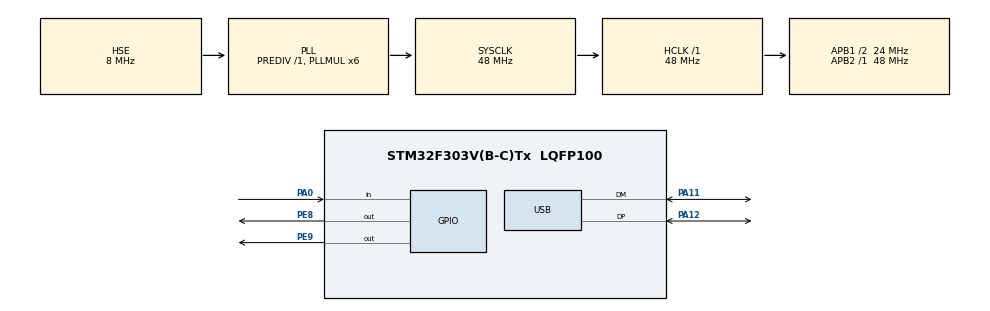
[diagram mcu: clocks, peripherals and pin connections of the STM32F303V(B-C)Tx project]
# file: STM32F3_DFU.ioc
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Mcu.Family=STM32F3
Mcu.Name=STM32F303V(B-C)Tx
Mcu.Package=LQFP100
NVIC.PriorityGroup=NVIC_PRIORITYGROUP_4
NVIC.USB_LP_CAN_RX0_IRQn=true\:0\:0\:false\:false\:true\:false\:true
PA0.GPIO_PuPd=GPIO_NOPULL
PA0.Signal=GPIO_Input
PA11.Mode=Device
PA11.Signal=USB_DM
PA12.Mode=Device
PA12.Signal=USB_DP
PE8.Signal=GPIO_Output
PE9.Signal=GPIO_Output
PF0-OSC_IN.Mode=HSE-External-Clock-Source
PF0-OSC_IN.Signal=RCC_OSC_IN
ProjectManager.HeapSize=0x200
ProjectManager.StackSize=0x400
ProjectManager.TargetToolchain=STM32CubeIDE
RCC.AHBFreq_Value=48000000
RCC.APB1CLKDivider=RCC_HCLK_DIV2
RCC.APB1Freq_Value=24000000
RCC.APB1TimFreq_Value=48000000
RCC.APB2Freq_Value=48000000
RCC.APB2TimFreq_Value=48000000
RCC.CortexFreq_Value=48000000
RCC.HCLKFreq_Value=48000000
RCC.HSE_VALUE=8000000
RCC.HSI_VALUE=8000000
RCC.LSE_VALUE=32768
RCC.PLLMUL=RCC_PLL_MUL6
RCC.SYSCLKFreq_VALUE=48000000
RCC.SYSCLKSourceVirtual=RCC_SYSCLKSOURCE_PLLCLK
RCC.USBFreq_Value=48000000
USB_DEVICE.CLASS_NAME_FS=DFU
USB_DEVICE.USBD_DFU_APP_DEFAULT_ADD=0x08006000
USB_DEVICE.USBD_DFU_MEDIA=@Internal Flash   /0x08000000/24*02Ka,232*02Kg
USB_DEVICE.VirtualMode=Dfu
USB_DEVICE.VirtualModeFS=Dfu_FS
VP_USB_DEVICE_VS_USB_DEVICE_DFU_FS.Mode=DFU_FS
board=custom

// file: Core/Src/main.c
/* USER CODE BEGIN Header */
/**
  ******************************************************************************
  * @file           : main.c
  * @brief          : Main program body
  ******************************************************************************
  * @attention
  *
  * <h2><center>&copy; Copyright (c) 2021 STMicroelectronics.
  * All rights reserved.</center></h2>
  *
  * This software component is licensed by ST under Ultimate Liberty license
  * SLA0044, the "License"; You may not use this file except in compliance with
  * the License. You may obtain a copy of the License at:
  *                             www.st.com/SLA0044
  *
  ******************************************************************************
  */
/* USER CODE END Header */
#include "main.h"
#include "usb_device.h"

/* USER CODE BEGIN PTD */
typedef  void (*pFunction)(void);
/* USER CODE END PTD */

void SystemClock_Config(void);
static void MX_GPIO_Init(void);

int main(void)
{
  /* USER CODE BEGIN 1 */
	  pFunction JumpToApplication;
	  uint32_t JumpAddress;
  /* USER CODE END 1 */

  /* MCU Configuration--------------------------------------------------------*/

  /* Reset of all peripherals, Initializes the Flash interface and the Systick. */
  HAL_Init();

  /* Configure the system clock */
  SystemClock_Config();

  /* Initialize all configured peripherals */
  MX_USB_DEVICE_Init();
  HAL_Delay(50);
  MX_GPIO_Init();
  /* USER CODE BEGIN 2 */
  if((GPIOA->IDR & GPIO_PIN_0) == 0)
  {
		JumpAddress = *(__IO uint32_t*) (USBD_DFU_APP_DEFAULT_ADD + 4);
		JumpToApplication = (pFunction) JumpAddress;

		/* Initialize user application's Stack Pointer */
		__set_MSP(*(__IO uint32_t*) USBD_DFU_APP_DEFAULT_ADD);
		JumpToApplication();
  }
  /* USER CODE END 2 */

  /* Infinite loop */
  while (1)
  {

    /* USER CODE BEGIN 3 */
	  GPIOE->ODR ^= (GPIO_PIN_9);
	  HAL_Delay(500);
  }
  /* USER CODE END 3 */
}

void SystemClock_Config(void)
{
  RCC_OscInitTypeDef RCC_OscInitStruct = {0};
  RCC_ClkInitTypeDef RCC_ClkInitStruct = {0};
  RCC_PeriphCLKInitTypeDef PeriphClkInit = {0};

  /** Initializes the RCC Oscillators according to the specified parameters
  * in the RCC_OscInitTypeDef structure.
  */
  RCC_OscInitStruct.OscillatorType = RCC_OSCILLATORTYPE_HSE;
  RCC_OscInitStruct.HSEState = RCC_HSE_BYPASS;
  RCC_OscInitStruct.HSEPredivValue = RCC_HSE_PREDIV_DIV1;
  RCC_OscInitStruct.HSIState = RCC_HSI_ON;
  RCC_OscInitStruct.PLL.PLLState = RCC_PLL_ON;
  RCC_OscInitStruct.PLL.PLLSource = RCC_PLLSOURCE_HSE;
  RCC_OscInitStruct.PLL.PLLMUL = RCC_PLL_MUL6;
  if (HAL_RCC_OscConfig(&RCC_OscInitStruct) != HAL_OK)
  {
    Error_Handler();
  }
  /** Initializes the CPU, AHB and APB buses clocks
  */
  RCC_ClkInitStruct.ClockType = RCC_CLOCKTYPE_HCLK|RCC_CLOCKTYPE_SYSCLK
                              |RCC_CLOCKTYPE_PCLK1|RCC_CLOCKTYPE_PCLK2;
  RCC_ClkInitStruct.SYSCLKSource = RCC_SYSCLKSOURCE_PLLCLK;
  RCC_ClkInitStruct.AHBCLKDivider = RCC_SYSCLK_DIV1;
  RCC_ClkInitStruct.APB1CLKDivider = RCC_HCLK_DIV2;
  RCC_ClkInitStruct.APB2CLKDivider = RCC_HCLK_DIV1;

  if (HAL_RCC_ClockConfig(&RCC_ClkInitStruct, FLASH_LATENCY_1) != HAL_OK)
  {
    Error_Handler();
  }
  PeriphClkInit.PeriphClockSelection = RCC_PERIPHCLK_USB;
  PeriphClkInit.USBClockSelection = RCC_USBCLKSOURCE_PLL;
  if (HAL_RCCEx_PeriphCLKConfig(&PeriphClkInit) != HAL_OK)
  {
    Error_Handler();
  }
}

static void MX_GPIO_Init(void)
{
  GPIO_InitTypeDef GPIO_InitStruct = {0};

  /* GPIO Ports Clock Enable */
  __HAL_RCC_GPIOF_CLK_ENABLE();
  __HAL_RCC_GPIOA_CLK_ENABLE();
  __HAL_RCC_GPIOE_CLK_ENABLE();

  /*Configure GPIO pin Output Level */
  HAL_GPIO_WritePin(GPIOE, GPIO_PIN_9|GPIO_PIN_10|GPIO_PIN_11|GPIO_PIN_12|GPIO_PIN_13|GPIO_PIN_14|GPIO_PIN_15, GPIO_PIN_RESET);

  /*Configure GPIO pin : PA0 */
  GPIO_InitStruct.Pin = GPIO_PIN_0;
  GPIO_InitStruct.Mode = GPIO_MODE_INPUT;
  GPIO_InitStruct.Pull = GPIO_NOPULL;
  HAL_GPIO_Init(GPIOA, &GPIO_InitStruct);

  /*Configure GPIO pins : PE8 PE9 */
  GPIO_InitStruct.Pin = GPIO_PIN_9|GPIO_PIN_10|GPIO_PIN_11|GPIO_PIN_12|GPIO_PIN_13|GPIO_PIN_14|GPIO_PIN_15;
  GPIO_InitStruct.Mode = GPIO_MODE_OUTPUT_PP;
  GPIO_InitStruct.Pull = GPIO_NOPULL;
  GPIO_InitStruct.Speed = GPIO_SPEED_FREQ_LOW;
  HAL_GPIO_Init(GPIOE, &GPIO_InitStruct);

}

void Error_Handler(void)
{
}

/************************ (C) COPYRIGHT STMicroelectronics *****END OF FILE****/
